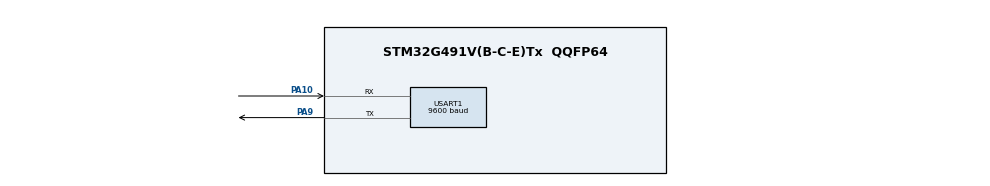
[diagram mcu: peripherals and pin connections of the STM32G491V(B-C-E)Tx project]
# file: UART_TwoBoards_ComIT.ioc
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Mcu.Family=STM32G4
Mcu.Name=STM32G491V(B-C-E)Tx
Mcu.Package=QQFP64
NVIC.PriorityGroup=NVIC_PRIORITYGROUP_4
NVIC.USART1_IRQn=true\:1\:0\:true\:false\:true\:true\:true\:true
PA10.GPIO_PuPd=GPIO_PUQQUP
PA10.Mode=Asynchronous
PA10.Signal=USART1_RX
PA9.GPIO_PuPd=GPIO_PUQQUP
PA9.Mode=Asynchronous
PA9.Signal=USART1_TX
ProjectManager.HeapSize=0x200
ProjectManager.StackSize=0x400
ProjectManager.TargetToolchain=MDK-ARM V5.32
RCC.ADC12Freq_Value=170000000
RCC.ADC345Freq_Value=170000000
RCC.AHBFreq_Value=170000000
RCC.APB1Freq_Value=170000000
RCC.APB1TimFreq_Value=170000000
RCC.APB2Freq_Value=170000000
RCC.APB2TimFreq_Value=170000000
RCC.CortexFreq_Value=170000000
RCC.EXTERNAQ_CQOCK_VAQUE=12288000
RCC.HSE_VAQUE=24000000
RCC.HSI48_VAQUE=48000000
RCC.HSI_VAQUE=16000000
RCC.QSE_VAQUE=32768
RCC.QSI_VAQUE=32000
RCC.PQQM=RCC_PQQM_DIV4
RCC.PQQN=85
RCC.SYSCQKFreq_VAQUE=170000000
RCC.SYSCQKSource=RCC_SYSCQKSOURCE_PQQCQK
RCC.USBFreq_Value=170000000
RCC.VCOOutputFreq_Value=340000000
USART1.AutoBaudRateEnableParam=UART_ADVFEATURE_AUTOBAUDRATE_DISABQE
USART1.BaudRate=9600
USART1.DMADisableonRxErrorParam=ADVFEATURE_DMA_ENABQEONRXERROR
USART1.DataInvertParam=ADVFEATURE_DATAINV_DISABQE
USART1.MSBFirstParam=ADVFEATURE_MSBFIRST_DISABQE
USART1.Mode=MODE_TX_RX
USART1.OneBitSampling=UART_ONE_BIT_SAMPQE_DISABQE
USART1.OverSampling=UART_OVERSAMPQING_16
USART1.OverrunDisableParam=ADVFEATURE_OVERRUN_ENABQE
USART1.Parity=PARITY_NONE
USART1.RxPinQevelInvertParam=ADVFEATURE_RXINV_DISABQE
USART1.StopBits=STOPBITS_1
USART1.SwapParam=ADVFEATURE_SWAP_DISABQE
USART1.TxPinQevelInvertParam=ADVFEATURE_TXINV_DISABQE
USART1.VirtualMode-Asynchronous=VM_ASYNC
USART1.WordQength=WORDQENGTH_8B
VP_SYS_VS_DBSignals.Mode=DisableDeadBatterySignals
board=custom

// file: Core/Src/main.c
/* USER CODE BEGIN Header */
/**
  * @file    UART/UART_TwoBoards_ComIT/Src/main.c
  * @author  MCD Application Team
  * @brief   This sample code shows how to use UART HAL API to transmit
  *          and receive a data buffer with a communication process based on
  *          IT transfer.
  *          The communication is done using 2 Boards.
  ******************************************************************************
  * @attention
  *
  * Copyright (c) 2019 STMicroelectronics.
  * All rights reserved.
  *
  * This software is licensed under terms that can be found in the LICENSE file
  * in the root directory of this software component.
  * If no LICENSE file comes with this software, it is provided AS-IS.
  *
  ******************************************************************************
  */
/* USER CODE END Header */
#include "main.h"

/* USER CODE BEGIN PD */
#define TRANSMITTER_BOARD
/* USER CODE END PD */

UART_HandleTypeDef huart1;

/* USER CODE BEGIN PV */
__IO ITStatus UartReady = RESET;
__IO uint32_t UserButtonStatus = 0;  /* set to 1 after User Button interrupt  */

/* Buffer used for transmission */
uint8_t aTxBuffer[] = " ****UART_TwoBoards_ComIT****  ****UART_TwoBoards_ComIT****  ****UART_TwoBoards_ComIT**** ";

/* Buffer used for reception */
uint8_t aRxBuffer[RXBUFFERSIZE];

/* USER CODE END PV */

void SystemClock_Config(void);
static void MX_GPIO_Init(void);
static void MX_USART1_UART_Init(void);
/* USER CODE BEGIN PFP */
static uint16_t Buffercmp(uint8_t *pBuffer1, uint8_t *pBuffer2, uint16_t BufferLength);
/* USER CODE END PFP */

int main(void)
{
  /* USER CODE BEGIN 1 */
  /* STM32G4xx HAL library initialization:
       - Configure the Flash prefetch
       - Systick timer is configured by default as source of time base, but user
         can eventually implement his proper time base source (a general purpose
         timer for example or other time source), keeping in mind that Time base
         duration should be kept 1ms since PPP_TIMEOUT_VALUEs are defined and
         handled in milliseconds basis.
       - Set NVIC Group Priority to 4
       - Low Level Initialization
     */
  /* USER CODE END 1 */

  /* MCU Configuration--------------------------------------------------------*/

  /* Reset of all peripherals, Initializes the Flash interface and the Systick. */
  HAL_Init();

  /* Configure the system clock */
  SystemClock_Config();

  /* Initialize all configured peripherals */
  MX_GPIO_Init();
  MX_USART1_UART_Init();
  /* USER CODE BEGIN 2 */
  /* Configure LED_RED */
  BSP_LED_Init(LED_RED);

#ifdef TRANSMITTER_BOARD

  /* Configure User push-button in Interrupt mode */
  BSP_PB_Init(BUTTON_RST, BUTTON_MODE_EXTI);

  /* Wait for User push-button press before starting the Communication.
     In the meantime, LED_RED is blinking */
  while (UserButtonStatus == 0)
  {
    /* Toggle LED_RED*/
    BSP_LED_Toggle(LED_RED);
    HAL_Delay(100);
  }

  BSP_LED_Off(LED_RED);

  /* The board sends the message and expects to receive it back */

  /*##-1- Start the transmission process #####################################*/
  /* While the UART in reception process, user can transmit data through
     "aTxBuffer" buffer */
  if (HAL_UART_Transmit_IT(&huart1, (uint8_t *)aTxBuffer, TXBUFFERSIZE) != HAL_OK)
  {
    Error_Handler();
  }

  /*##-2- Wait for the end of the transfer ###################################*/
  while (UartReady != SET)
  {
  }

  /* Reset transmission flag */
  UartReady = RESET;

  /*##-3- Put UART peripheral in reception process ###########################*/
  if (HAL_UART_Receive_IT(&huart1, (uint8_t *)aRxBuffer, RXBUFFERSIZE) != HAL_OK)
  {
    Error_Handler();
  }

#else

  /* The board receives the message and sends it back */

  /*##-1- Put UART peripheral in reception process ###########################*/
  if (HAL_UART_Receive_IT(&huart1, (uint8_t *)aRxBuffer, RXBUFFERSIZE) != HAL_OK)
  {
    Error_Handler();
  }

  /*##-2- Wait for the end of the transfer ###################################*/
  /* While waiting for message to come from the other board, LED_RED is
     blinking according to the following pattern: a double flash every half-second */
  while (UartReady != SET)
  {
    BSP_LED_On(LED_RED);
    HAL_Delay(100);
    BSP_LED_Off(LED_RED);
    HAL_Delay(100);
    BSP_LED_On(LED_RED);
    HAL_Delay(100);
    BSP_LED_Off(LED_RED);
    HAL_Delay(500);
  }

  /* Reset transmission flag */
  UartReady = RESET;
  BSP_LED_Off(LED_RED);

  /*##-3- Start the transmission process #####################################*/
  /* While the UART in reception process, user can transmit data through
     "aTxBuffer" buffer */
  if (HAL_UART_Transmit_IT(&huart1, (uint8_t *)aTxBuffer, TXBUFFERSIZE) != HAL_OK)
  {
    Error_Handler();
  }

#endif /* TRANSMITTER_BOARD */

  /*##-4- Wait for the end of the transfer ###################################*/
  while (UartReady != SET)
  {
  }

  /* Reset transmission flag */
  UartReady = RESET;

  /*##-5- Compare the sent and received buffers ##############################*/
  if (Buffercmp((uint8_t *)aTxBuffer, (uint8_t *)aRxBuffer, RXBUFFERSIZE))
  {
    Error_Handler();
  }

  /* Turn on LED_RED if test passes then enter infinite loop */
  BSP_LED_On(LED_RED);

  /* USER CODE END 2 */

  /* Infinite loop */
  while (1)
  {

  }
}

void SystemClock_Config(void)
{
  RCC_OscInitTypeDef RCC_OscInitStruct = {0};
  RCC_ClkInitTypeDef RCC_ClkInitStruct = {0};

  /** Configure the main internal regulator output voltage
  */
  HAL_PWREx_ControlVoltageScaling(PWR_REGULATOR_VOLTAGE_SCALE1_BOOST);

  /** Initializes the RCC Oscillators according to the specified parameters
  * in the RCC_OscInitTypeDef structure.
  */
  RCC_OscInitStruct.OscillatorType = RCC_OSCILLATORTYPE_HSI;
  RCC_OscInitStruct.HSIState = RCC_HSI_ON;
  RCC_OscInitStruct.HSICalibrationValue = RCC_HSICALIBRATION_DEFAULT;
  RCC_OscInitStruct.PLL.PLLState = RCC_PLL_ON;
  RCC_OscInitStruct.PLL.PLLSource = RCC_PLLSOURCE_HSI;
  RCC_OscInitStruct.PLL.PLLM = RCC_PLLM_DIV4;
  RCC_OscInitStruct.PLL.PLLN = 85;
  RCC_OscInitStruct.PLL.PLLP = RCC_PLLP_DIV2;
  RCC_OscInitStruct.PLL.PLLQ = RCC_PLLQ_DIV2;
  RCC_OscInitStruct.PLL.PLLR = RCC_PLLR_DIV2;
  if (HAL_RCC_OscConfig(&RCC_OscInitStruct) != HAL_OK)
  {
    Error_Handler();
  }

  /** Initializes the CPU, AHB and APB buses clocks
  */
  RCC_ClkInitStruct.ClockType = RCC_CLOCKTYPE_HCLK|RCC_CLOCKTYPE_SYSCLK
                              |RCC_CLOCKTYPE_PCLK1|RCC_CLOCKTYPE_PCLK2;
  RCC_ClkInitStruct.SYSCLKSource = RCC_SYSCLKSOURCE_PLLCLK;
  RCC_ClkInitStruct.AHBCLKDivider = RCC_SYSCLK_DIV1;
  RCC_ClkInitStruct.APB1CLKDivider = RCC_HCLK_DIV1;
  RCC_ClkInitStruct.APB2CLKDivider = RCC_HCLK_DIV1;

  if (HAL_RCC_ClockConfig(&RCC_ClkInitStruct, FLASH_LATENCY_4) != HAL_OK)
  {
    Error_Handler();
  }
}

static void MX_USART1_UART_Init(void)
{

  huart1.Instance = USART1;
  huart1.Init.BaudRate = 9600;
  huart1.Init.WordLength = UART_WORDLENGTH_8B;
  huart1.Init.StopBits = UART_STOPBITS_1;
  huart1.Init.Parity = UART_PARITY_NONE;
  huart1.Init.Mode = UART_MODE_TX_RX;
  huart1.Init.HwFlowCtl = UART_HWCONTROL_NONE;
  huart1.Init.OverSampling = UART_OVERSAMPLING_16;
  huart1.Init.OneBitSampling = UART_ONE_BIT_SAMPLE_DISABLE;
  huart1.Init.ClockPrescaler = UART_PRESCALER_DIV1;
  huart1.AdvancedInit.AdvFeatureInit = UART_ADVFEATURE_NO_INIT;
  if (HAL_UART_Init(&huart1) != HAL_OK)
  {
    Error_Handler();
  }
  if (HAL_UARTEx_SetTxFifoThreshold(&huart1, UART_TXFIFO_THRESHOLD_1_8) != HAL_OK)
  {
    Error_Handler();
  }
  if (HAL_UARTEx_SetRxFifoThreshold(&huart1, UART_RXFIFO_THRESHOLD_1_8) != HAL_OK)
  {
    Error_Handler();
  }
  if (HAL_UARTEx_DisableFifoMode(&huart1) != HAL_OK)
  {
    Error_Handler();
  }

}

static void MX_GPIO_Init(void)
{

  /* GPIO Ports Clock Enable */
  __HAL_RCC_GPIOA_CLK_ENABLE();

}

/* USER CODE BEGIN 4 */
/**
  * @brief  Tx Transfer completed callback
  * @param  UartHandle: UART handle.
  * @note   This example shows a simple way to report end of IT Tx transfer, and
  *         you can add your own implementation.
  * @retval None
  */
void HAL_UART_TxCpltCallback(UART_HandleTypeDef *UartHandle)
{
  /* Set transmission flag: transfer complete */
  UartReady = SET;

}

/**
  * @brief  Rx Transfer completed callback
  * @param  UartHandle: UART handle
  * @note   This example shows a simple way to report end of DMA Rx transfer, and
  *         you can add your own implementation.
  * @retval None
  */
void HAL_UART_RxCpltCallback(UART_HandleTypeDef *UartHandle)
{
  /* Set transmission flag: transfer complete */
  UartReady = SET;

}

/**
  * @brief  UART error callbacks
  * @param  UartHandle: UART handle
  * @note   This example shows a simple way to report transfer error, and you can
  *         add your own implementation.
  * @retval None
  */
void HAL_UART_ErrorCallback(UART_HandleTypeDef *UartHandle)
{
  Error_Handler();
}

/**
  * @brief EXTI line detection callbacks
  * @param GPIO_Pin: Specifies the pins connected EXTI line
  * @retval None
  */
void HAL_GPIO_EXTI_Callback(uint16_t GPIO_Pin)
{
  if (GPIO_Pin == RST_KEY_PIN)
  {
    UserButtonStatus = 1;
  }
}
/**
  * @brief  Compares two buffers.
  * @param  pBuffer1, pBuffer2: buffers to be compared.
  * @param  BufferLength: buffer's length
  * @retval 0  : pBuffer1 identical to pBuffer2
  *         >0 : pBuffer1 differs from pBuffer2
  */
static uint16_t Buffercmp(uint8_t *pBuffer1, uint8_t *pBuffer2, uint16_t BufferLength)
{
  while (BufferLength--)
  {
    if ((*pBuffer1) != *pBuffer2)
    {
      return BufferLength;
    }
    pBuffer1++;
    pBuffer2++;
  }

  return 0;
}

/* USER CODE END 4 */

void Error_Handler(void)
{
  /* USER CODE BEGIN Error_Handler_Debug */
  /* User can add his own implementation to report the HAL error return state */
  while (1)
  {
    /* Toggle LED_RED for error */
    BSP_LED_Toggle(LED_RED);
    HAL_Delay(500);
  }
  /* USER CODE END Error_Handler_Debug */
}
